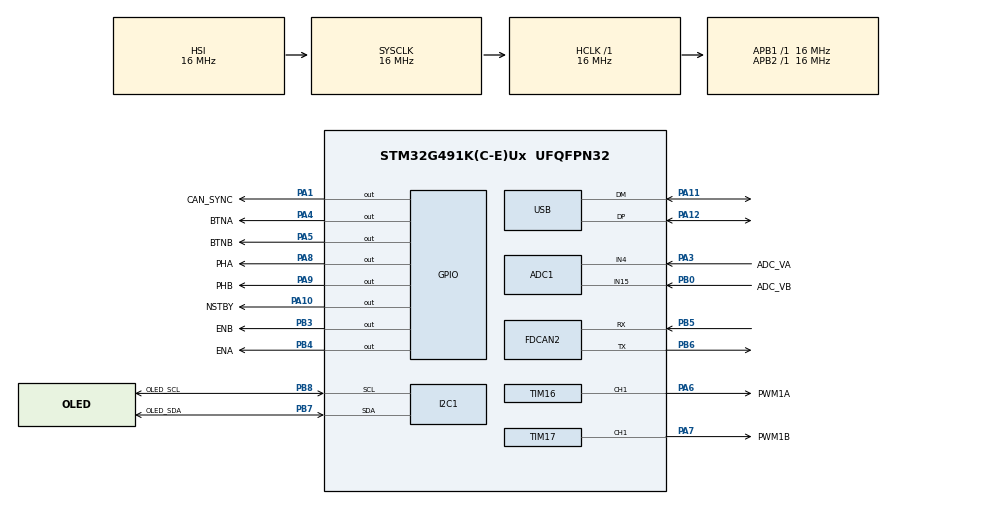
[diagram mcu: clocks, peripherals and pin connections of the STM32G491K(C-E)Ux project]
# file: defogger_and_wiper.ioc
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ADC1.Channel-1\#ChannelRegularConversion=ADC_CHANNEL_15
ADC1.NbrOfConversionFlag=1
ADC1.OffsetNumber-1\#ChannelRegularConversion=ADC_OFFSET_NONE
ADC1.Rank-1\#ChannelRegularConversion=1
ADC1.SamplingTime-1\#ChannelRegularConversion=ADC_SAMPLETIME_2CYCLES_5
ADC1.master=1
FDCAN2.CalculateBaudRateNominal=333333
FDCAN2.CalculateTimeBitNominal=3000
FDCAN2.CalculateTimeQuantumNominal=1000.0
I2C1.Timing=0x00503D58
Mcu.Family=STM32G4
Mcu.Name=STM32G491K(C-E)Ux
Mcu.Package=UFQFPN32
NVIC.PriorityGroup=NVIC_PRIORITYGROUP_4
PA1.GPIO_Label=CAN_SYNC
PA1.Signal=GPIO_Output
PA10.GPIO_Label=NSTBY
PA10.Signal=GPIO_Output
PA11.Mode=Device
PA11.Signal=USB_DM
PA12.Mode=Device
PA12.Signal=USB_DP
PA13.Signal=SYS_JTMS-SWDIO
PA14.Signal=SYS_JTCK-SWCLK
PA15.GPIO_Label=RGB_TIM
PA15.Signal=S_TIM2_CH1
PA3.GPIO_Label=ADC_VA
PA3.Mode=IN4-Single-Ended
PA3.Signal=ADC1_IN4
PA4.GPIO_Label=BTNA
PA4.Signal=GPIO_Output
PA5.GPIO_Label=BTNB
PA5.Signal=GPIO_Output
PA6.GPIO_Label=PWM1A
PA6.Signal=S_TIM16_CH1
PA7.GPIO_Label=PWM1B
PA7.Signal=S_TIM17_CH1
PA8.GPIO_Label=PHA
PA8.Signal=GPIO_Output
PA9.GPIO_Label=PHB
PA9.Signal=GPIO_Output
PB0.GPIO_Label=ADC_VB
PB0.Mode=IN15-Single-Ended
PB0.Signal=ADC1_IN15
PB3.GPIO_Label=ENB
PB3.Signal=GPIO_Output
PB4.GPIO_Label=ENA
PB4.Signal=GPIO_Output
PB5.Mode=FDCAN_Activate
PB5.Signal=FDCAN2_RX
PB6.Mode=FDCAN_Activate
PB6.Signal=FDCAN2_TX
PB7.GPIO_Label=OLED_SDA
PB7.Mode=I2C
PB7.Signal=I2C1_SDA
PB8-BOOT0.GPIO_Label=OLED_SCL
PB8-BOOT0.Mode=I2C
PB8-BOOT0.Signal=I2C1_SCL
PF0-OSC_IN.Mode=HSE-External-Oscillator
PF0-OSC_IN.Signal=RCC_OSC_IN
PF1-OSC_OUT.Mode=HSE-External-Oscillator
PF1-OSC_OUT.Signal=RCC_OSC_OUT
ProjectManager.HeapSize=0x200
ProjectManager.StackSize=0x400
ProjectManager.TargetToolchain=STM32CubeIDE
RCC.AHBFreq_Value=16000000
RCC.APB1Freq_Value=16000000
RCC.APB1TimFreq_Value=16000000
RCC.APB2Freq_Value=16000000
RCC.APB2TimFreq_Value=16000000
RCC.CortexFreq_Value=16000000
RCC.EXTERNAL_CLOCK_VALUE=12288000
RCC.HCLKFreq_Value=16000000
RCC.HSE_VALUE=8000000
RCC.HSI48_VALUE=48000000
RCC.HSI_VALUE=16000000
RCC.LSE_VALUE=32768
RCC.SYSCLKFreq_VALUE=16000000
RCC.VCOOutputFreq_Value=128000000
SH.S_TIM16_CH1.0=TIM16_CH1,PWM Generation1 CH1
SH.S_TIM17_CH1.0=TIM17_CH1,PWM Generation1 CH1
SH.S_TIM2_CH1.0=TIM2_CH1
TIM16.Channel=TIM_CHANNEL_1
TIM17.Channel=TIM_CHANNEL_1
VP_SYS_VS_DBSignals.Mode=DisableDeadBatterySignals
VP_TIM16_VS_ClockSourceINT.Mode=Enable_Timer
VP_TIM17_VS_ClockSourceINT.Mode=Enable_Timer
board=custom

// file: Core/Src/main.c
/* USER CODE BEGIN Header */
/**
  ******************************************************************************
  * @file           : main.c
  * @brief          : Main program body
  ******************************************************************************
  * @attention
  *
  * Copyright (c) 2025 STMicroelectronics.
  * All rights reserved.
  *
  * This software is licensed under terms that can be found in the LICENSE file
  * in the root directory of this software component.
  * If no LICENSE file comes with this software, it is provided AS-IS.
  *
  ******************************************************************************
  */
/* USER CODE END Header */
#include "main.h"

ADC_HandleTypeDef hadc1;

FDCAN_HandleTypeDef hfdcan2;

I2C_HandleTypeDef hi2c1;

TIM_HandleTypeDef htim16;
TIM_HandleTypeDef htim17;

PCD_HandleTypeDef hpcd_USB_FS;

void SystemClock_Config(void);
static void MX_GPIO_Init(void);
static void MX_ADC1_Init(void);
static void MX_I2C1_Init(void);
static void MX_FDCAN2_Init(void);
static void MX_TIM16_Init(void);
static void MX_TIM17_Init(void);
static void MX_USB_PCD_Init(void);

int main(void)
{

  /* MCU Configuration--------------------------------------------------------*/

  /* Reset of all peripherals, Initializes the Flash interface and the Systick. */
  HAL_Init();

  /* Configure the system clock */
  SystemClock_Config();

  /* Initialize all configured peripherals */
  MX_GPIO_Init();
  MX_ADC1_Init();
  MX_I2C1_Init();
  MX_FDCAN2_Init();
  MX_TIM16_Init();
  MX_TIM17_Init();
  MX_USB_PCD_Init();

  /* Infinite loop */
  while (1)
  {

  }
}

void SystemClock_Config(void)
{
  RCC_OscInitTypeDef RCC_OscInitStruct = {0};
  RCC_ClkInitTypeDef RCC_ClkInitStruct = {0};

  /** Configure the main internal regulator output voltage
  */
  HAL_PWREx_ControlVoltageScaling(PWR_REGULATOR_VOLTAGE_SCALE1);

  /** Initializes the RCC Oscillators according to the specified parameters
  * in the RCC_OscInitTypeDef structure.
  */
  RCC_OscInitStruct.OscillatorType = RCC_OSCILLATORTYPE_HSI|RCC_OSCILLATORTYPE_HSI48;
  RCC_OscInitStruct.HSIState = RCC_HSI_ON;
  RCC_OscInitStruct.HSICalibrationValue = RCC_HSICALIBRATION_DEFAULT;
  RCC_OscInitStruct.HSI48State = RCC_HSI48_ON;
  RCC_OscInitStruct.PLL.PLLState = RCC_PLL_NONE;
  if (HAL_RCC_OscConfig(&RCC_OscInitStruct) != HAL_OK)
  {
    Error_Handler();
  }

  /** Initializes the CPU, AHB and APB buses clocks
  */
  RCC_ClkInitStruct.ClockType = RCC_CLOCKTYPE_HCLK|RCC_CLOCKTYPE_SYSCLK
                              |RCC_CLOCKTYPE_PCLK1|RCC_CLOCKTYPE_PCLK2;
  RCC_ClkInitStruct.SYSCLKSource = RCC_SYSCLKSOURCE_HSI;
  RCC_ClkInitStruct.AHBCLKDivider = RCC_SYSCLK_DIV1;
  RCC_ClkInitStruct.APB1CLKDivider = RCC_HCLK_DIV1;
  RCC_ClkInitStruct.APB2CLKDivider = RCC_HCLK_DIV1;

  if (HAL_RCC_ClockConfig(&RCC_ClkInitStruct, FLASH_LATENCY_0) != HAL_OK)
  {
    Error_Handler();
  }
}

static void MX_ADC1_Init(void)
{

  ADC_MultiModeTypeDef multimode = {0};
  ADC_ChannelConfTypeDef sConfig = {0};

  /** Common config
  */
  hadc1.Instance = ADC1;
  hadc1.Init.ClockPrescaler = ADC_CLOCK_SYNC_PCLK_DIV2;
  hadc1.Init.Resolution = ADC_RESOLUTION_12B;
  hadc1.Init.DataAlign = ADC_DATAALIGN_RIGHT;
  hadc1.Init.GainCompensation = 0;
  hadc1.Init.ScanConvMode = ADC_SCAN_DISABLE;
  hadc1.Init.EOCSelection = ADC_EOC_SINGLE_CONV;
  hadc1.Init.LowPowerAutoWait = DISABLE;
  hadc1.Init.ContinuousConvMode = DISABLE;
  hadc1.Init.NbrOfConversion = 1;
  hadc1.Init.DiscontinuousConvMode = DISABLE;
  hadc1.Init.ExternalTrigConv = ADC_SOFTWARE_START;
  hadc1.Init.ExternalTrigConvEdge = ADC_EXTERNALTRIGCONVEDGE_NONE;
  hadc1.Init.DMAContinuousRequests = DISABLE;
  hadc1.Init.Overrun = ADC_OVR_DATA_PRESERVED;
  hadc1.Init.OversamplingMode = DISABLE;
  if (HAL_ADC_Init(&hadc1) != HAL_OK)
  {
    Error_Handler();
  }

  /** Configure the ADC multi-mode
  */
  multimode.Mode = ADC_MODE_INDEPENDENT;
  if (HAL_ADCEx_MultiModeConfigChannel(&hadc1, &multimode) != HAL_OK)
  {
    Error_Handler();
  }

  /** Configure Regular Channel
  */
  sConfig.Channel = ADC_CHANNEL_15;
  sConfig.Rank = ADC_REGULAR_RANK_1;
  sConfig.SamplingTime = ADC_SAMPLETIME_2CYCLES_5;
  sConfig.SingleDiff = ADC_SINGLE_ENDED;
  sConfig.OffsetNumber = ADC_OFFSET_NONE;
  sConfig.Offset = 0;
  if (HAL_ADC_ConfigChannel(&hadc1, &sConfig) != HAL_OK)
  {
    Error_Handler();
  }

}

static void MX_FDCAN2_Init(void)
{

  hfdcan2.Instance = FDCAN2;
  hfdcan2.Init.ClockDivider = FDCAN_CLOCK_DIV1;
  hfdcan2.Init.FrameFormat = FDCAN_FRAME_CLASSIC;
  hfdcan2.Init.Mode = FDCAN_MODE_NORMAL;
  hfdcan2.Init.AutoRetransmission = DISABLE;
  hfdcan2.Init.TransmitPause = DISABLE;
  hfdcan2.Init.ProtocolException = DISABLE;
  hfdcan2.Init.NominalPrescaler = 16;
  hfdcan2.Init.NominalSyncJumpWidth = 1;
  hfdcan2.Init.NominalTimeSeg1 = 1;
  hfdcan2.Init.NominalTimeSeg2 = 1;
  hfdcan2.Init.DataPrescaler = 1;
  hfdcan2.Init.DataSyncJumpWidth = 1;
  hfdcan2.Init.DataTimeSeg1 = 1;
  hfdcan2.Init.DataTimeSeg2 = 1;
  hfdcan2.Init.StdFiltersNbr = 0;
  hfdcan2.Init.ExtFiltersNbr = 0;
  hfdcan2.Init.TxFifoQueueMode = FDCAN_TX_FIFO_OPERATION;
  if (HAL_FDCAN_Init(&hfdcan2) != HAL_OK)
  {
    Error_Handler();
  }

}

static void MX_I2C1_Init(void)
{

  hi2c1.Instance = I2C1;
  hi2c1.Init.Timing = 0x00503D58;
  hi2c1.Init.OwnAddress1 = 0;
  hi2c1.Init.AddressingMode = I2C_ADDRESSINGMODE_7BIT;
  hi2c1.Init.DualAddressMode = I2C_DUALADDRESS_DISABLE;
  hi2c1.Init.OwnAddress2 = 0;
  hi2c1.Init.OwnAddress2Masks = I2C_OA2_NOMASK;
  hi2c1.Init.GeneralCallMode = I2C_GENERALCALL_DISABLE;
  hi2c1.Init.NoStretchMode = I2C_NOSTRETCH_DISABLE;
  if (HAL_I2C_Init(&hi2c1) != HAL_OK)
  {
    Error_Handler();
  }

  /** Configure Analogue filter
  */
  if (HAL_I2CEx_ConfigAnalogFilter(&hi2c1, I2C_ANALOGFILTER_ENABLE) != HAL_OK)
  {
    Error_Handler();
  }

  /** Configure Digital filter
  */
  if (HAL_I2CEx_ConfigDigitalFilter(&hi2c1, 0) != HAL_OK)
  {
    Error_Handler();
  }

}

static void MX_TIM16_Init(void)
{

  TIM_OC_InitTypeDef sConfigOC = {0};
  TIM_BreakDeadTimeConfigTypeDef sBreakDeadTimeConfig = {0};

  htim16.Instance = TIM16;
  htim16.Init.Prescaler = 0;
  htim16.Init.CounterMode = TIM_COUNTERMODE_UP;
  htim16.Init.Period = 65535;
  htim16.Init.ClockDivision = TIM_CLOCKDIVISION_DIV1;
  htim16.Init.RepetitionCounter = 0;
  htim16.Init.AutoReloadPreload = TIM_AUTORELOAD_PRELOAD_DISABLE;
  if (HAL_TIM_Base_Init(&htim16) != HAL_OK)
  {
    Error_Handler();
  }
  if (HAL_TIM_PWM_Init(&htim16) != HAL_OK)
  {
    Error_Handler();
  }
  sConfigOC.OCMode = TIM_OCMODE_PWM1;
  sConfigOC.Pulse = 0;
  sConfigOC.OCPolarity = TIM_OCPOLARITY_HIGH;
  sConfigOC.OCNPolarity = TIM_OCNPOLARITY_HIGH;
  sConfigOC.OCFastMode = TIM_OCFAST_DISABLE;
  sConfigOC.OCIdleState = TIM_OCIDLESTATE_RESET;
  sConfigOC.OCNIdleState = TIM_OCNIDLESTATE_RESET;
  if (HAL_TIM_PWM_ConfigChannel(&htim16, &sConfigOC, TIM_CHANNEL_1) != HAL_OK)
  {
    Error_Handler();
  }
  sBreakDeadTimeConfig.OffStateRunMode = TIM_OSSR_DISABLE;
  sBreakDeadTimeConfig.OffStateIDLEMode = TIM_OSSI_DISABLE;
  sBreakDeadTimeConfig.LockLevel = TIM_LOCKLEVEL_OFF;
  sBreakDeadTimeConfig.DeadTime = 0;
  sBreakDeadTimeConfig.BreakState = TIM_BREAK_DISABLE;
  sBreakDeadTimeConfig.BreakPolarity = TIM_BREAKPOLARITY_HIGH;
  sBreakDeadTimeConfig.BreakFilter = 0;
  sBreakDeadTimeConfig.AutomaticOutput = TIM_AUTOMATICOUTPUT_DISABLE;
  if (HAL_TIMEx_ConfigBreakDeadTime(&htim16, &sBreakDeadTimeConfig) != HAL_OK)
  {
    Error_Handler();
  }
  HAL_TIM_MspPostInit(&htim16);

}

static void MX_TIM17_Init(void)
{

  TIM_OC_InitTypeDef sConfigOC = {0};
  TIM_BreakDeadTimeConfigTypeDef sBreakDeadTimeConfig = {0};

  htim17.Instance = TIM17;
  htim17.Init.Prescaler = 0;
  htim17.Init.CounterMode = TIM_COUNTERMODE_UP;
  htim17.Init.Period = 65535;
  htim17.Init.ClockDivision = TIM_CLOCKDIVISION_DIV1;
  htim17.Init.RepetitionCounter = 0;
  htim17.Init.AutoReloadPreload = TIM_AUTORELOAD_PRELOAD_DISABLE;
  if (HAL_TIM_Base_Init(&htim17) != HAL_OK)
  {
    Error_Handler();
  }
  if (HAL_TIM_PWM_Init(&htim17) != HAL_OK)
  {
    Error_Handler();
  }
  sConfigOC.OCMode = TIM_OCMODE_PWM1;
  sConfigOC.Pulse = 0;
  sConfigOC.OCPolarity = TIM_OCPOLARITY_HIGH;
  sConfigOC.OCNPolarity = TIM_OCNPOLARITY_HIGH;
  sConfigOC.OCFastMode = TIM_OCFAST_DISABLE;
  sConfigOC.OCIdleState = TIM_OCIDLESTATE_RESET;
  sConfigOC.OCNIdleState = TIM_OCNIDLESTATE_RESET;
  if (HAL_TIM_PWM_ConfigChannel(&htim17, &sConfigOC, TIM_CHANNEL_1) != HAL_OK)
  {
    Error_Handler();
  }
  sBreakDeadTimeConfig.OffStateRunMode = TIM_OSSR_DISABLE;
  sBreakDeadTimeConfig.OffStateIDLEMode = TIM_OSSI_DISABLE;
  sBreakDeadTimeConfig.LockLevel = TIM_LOCKLEVEL_OFF;
  sBreakDeadTimeConfig.DeadTime = 0;
  sBreakDeadTimeConfig.BreakState = TIM_BREAK_DISABLE;
  sBreakDeadTimeConfig.BreakPolarity = TIM_BREAKPOLARITY_HIGH;
  sBreakDeadTimeConfig.BreakFilter = 0;
  sBreakDeadTimeConfig.AutomaticOutput = TIM_AUTOMATICOUTPUT_DISABLE;
  if (HAL_TIMEx_ConfigBreakDeadTime(&htim17, &sBreakDeadTimeConfig) != HAL_OK)
  {
    Error_Handler();
  }
  HAL_TIM_MspPostInit(&htim17);

}

static void MX_USB_PCD_Init(void)
{

  hpcd_USB_FS.Instance = USB;
  hpcd_USB_FS.Init.dev_endpoints = 8;
  hpcd_USB_FS.Init.speed = PCD_SPEED_FULL;
  hpcd_USB_FS.Init.phy_itface = PCD_PHY_EMBEDDED;
  hpcd_USB_FS.Init.Sof_enable = DISABLE;
  hpcd_USB_FS.Init.low_power_enable = DISABLE;
  hpcd_USB_FS.Init.lpm_enable = DISABLE;
  hpcd_USB_FS.Init.battery_charging_enable = DISABLE;
  if (HAL_PCD_Init(&hpcd_USB_FS) != HAL_OK)
  {
    Error_Handler();
  }

}

static void MX_GPIO_Init(void)
{
  GPIO_InitTypeDef GPIO_InitStruct = {0};

  /* GPIO Ports Clock Enable */
  __HAL_RCC_GPIOF_CLK_ENABLE();
  __HAL_RCC_GPIOA_CLK_ENABLE();
  __HAL_RCC_GPIOB_CLK_ENABLE();

  /*Configure GPIO pin Output Level */
  HAL_GPIO_WritePin(GPIOA, CAN_SYNC_Pin|PIN1_Pin|PIN2_Pin|PHA_Pin
                          |PHB_Pin|NSTBY_Pin|PIN3_Pin, GPIO_PIN_RESET);

  /*Configure GPIO pin Output Level */
  HAL_GPIO_WritePin(GPIOB, ENB_Pin|ENA_Pin, GPIO_PIN_RESET);

  /*Configure GPIO pins : CAN_SYNC_Pin PIN1_Pin PIN2_Pin PHA_Pin
                           PHB_Pin NSTBY_Pin PIN3_Pin */
  GPIO_InitStruct.Pin = CAN_SYNC_Pin|PIN1_Pin|PIN2_Pin|PHA_Pin
                          |PHB_Pin|NSTBY_Pin|PIN3_Pin;
  GPIO_InitStruct.Mode = GPIO_MODE_OUTPUT_PP;
  GPIO_InitStruct.Pull = GPIO_NOPULL;
  GPIO_InitStruct.Speed = GPIO_SPEED_FREQ_LOW;
  HAL_GPIO_Init(GPIOA, &GPIO_InitStruct);

  /*Configure GPIO pins : ENB_Pin ENA_Pin */
  GPIO_InitStruct.Pin = ENB_Pin|ENA_Pin;
  GPIO_InitStruct.Mode = GPIO_MODE_OUTPUT_PP;
  GPIO_InitStruct.Pull = GPIO_NOPULL;
  GPIO_InitStruct.Speed = GPIO_SPEED_FREQ_LOW;
  HAL_GPIO_Init(GPIOB, &GPIO_InitStruct);

}

void Error_Handler(void)
{
  __disable_irq();
  while (1)
  {
  }
}
